# STM32L4P5AEI6 register map
File version: 1.0
Registers are 32-bit, access not given, reset 0x0 unless marked. A register's access mark holds for its fields unless they carry their own. Offsets are from the block's base; [hi:lo] are bit positions; 'fields as' and 'values as' point back to an identical list.

## DMA2D
Base 0x4002B000
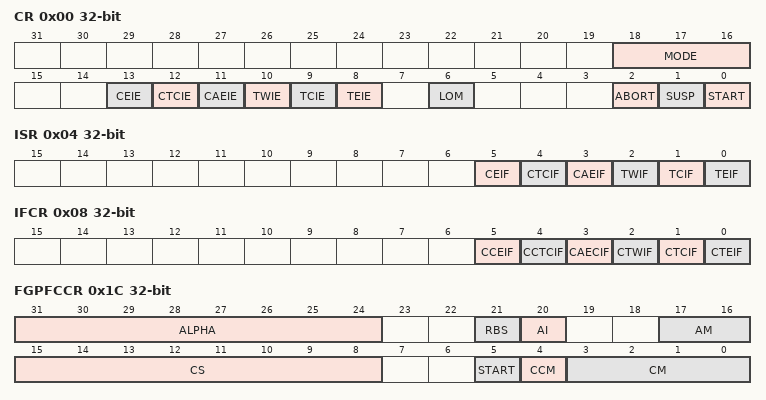
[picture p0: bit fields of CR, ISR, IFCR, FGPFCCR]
0x00 CR
  [18:16] MODE, [13] CEIE, [12] CTCIE, [11] CAEIE, [10] TWIE, [9] TCIE, [8] TEIE, [6] LOM, [2] ABORT, [1] SUSP, [0] START
0x04 ISR
  [5] CEIF, [4] CTCIF, [3] CAEIF, [2] TWIF, [1] TCIF, [0] TEIF
0x08 IFCR
  [5] CCEIF, [4] CCTCIF, [3] CAECIF, [2] CTWIF, [1] CTCIF, [0] CTEIF
0x0C FGMAR
  [31:0] MA
0x10 FGOR
  [15:0] LO
0x14 BGMAR
  [31:0] MA
0x18 BGOR
  [15:0] LO
0x1C FGPFCCR
  [31:24] ALPHA, [21] RBS, [20] AI, [17:16] AM, [15:8] CS, [5] START, [4] CCM, [3:0] CM
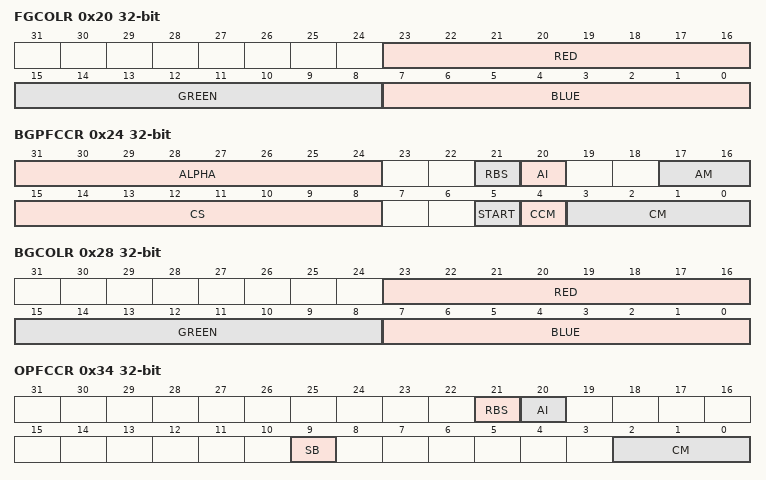
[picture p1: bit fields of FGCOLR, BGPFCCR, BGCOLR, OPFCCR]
0x20 FGCOLR
  [23:16] RED, [15:8] GREEN, [7:0] BLUE
0x24 BGPFCCR
  fields as FGPFCCR
0x28 BGCOLR
  [23:16] RED, [15:8] GREEN, [7:0] BLUE
0x2C FGCMAR
  [31:0] MA
0x30 BGCMAR
  [31:0] MA
0x34 OPFCCR
  [21] RBS, [20] AI, [9] SB, [2:0] CM
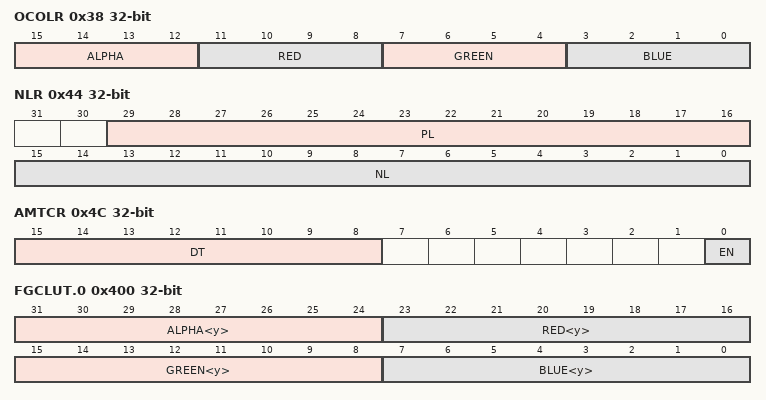
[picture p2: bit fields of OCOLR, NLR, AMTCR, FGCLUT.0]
0x38 OCOLR
  [15:12] ALPHA, [11:8] RED, [7:4] GREEN, [3:0] BLUE
0x3C OMAR
  [31:0] MA
0x40 OOR
  [15:0] LO
0x44 NLR
  [29:16] PL, [15:0] NL
0x48 LWR
  [15:0] LW
0x4C AMTCR
  [15:8] DT, [0] EN
0x400 FGCLUT.0
  [31:24] ALPHA<y>, [23:16] RED<y>, [15:8] GREEN<y>, [7:0] BLUE<y>
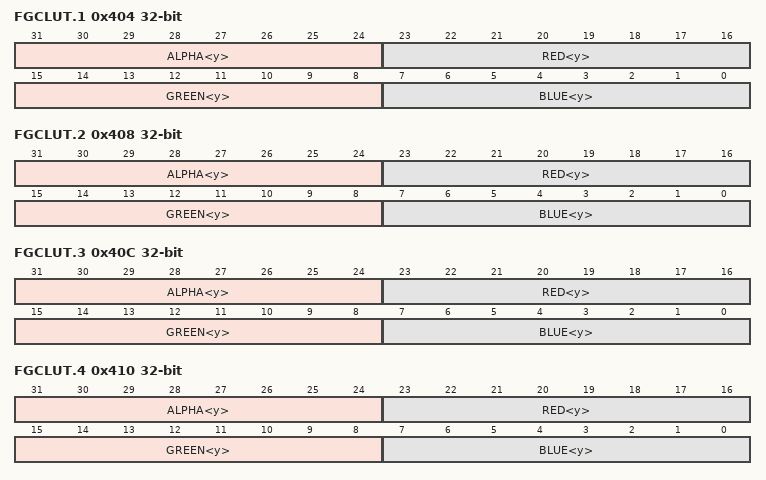
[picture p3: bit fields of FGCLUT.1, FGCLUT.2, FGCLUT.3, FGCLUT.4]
0x404 FGCLUT.1
  [31:24] ALPHA<y>, [23:16] RED<y>, [15:8] GREEN<y>, [7:0] BLUE<y>
0x408 FGCLUT.2
  [31:24] ALPHA<y>, [23:16] RED<y>, [15:8] GREEN<y>, [7:0] BLUE<y>
0x40C FGCLUT.3
  [31:24] ALPHA<y>, [23:16] RED<y>, [15:8] GREEN<y>, [7:0] BLUE<y>
0x410 FGCLUT.4
  [31:24] ALPHA<y>, [23:16] RED<y>, [15:8] GREEN<y>, [7:0] BLUE<y>
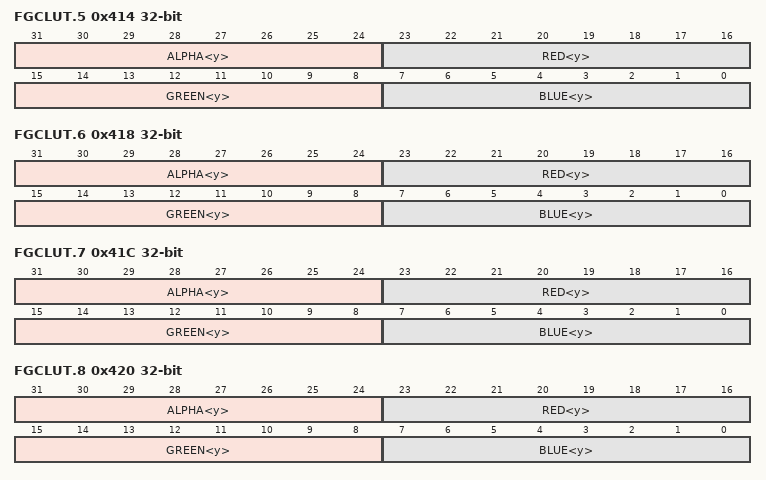
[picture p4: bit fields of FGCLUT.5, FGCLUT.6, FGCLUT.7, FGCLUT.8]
0x414 FGCLUT.5
  [31:24] ALPHA<y>, [23:16] RED<y>, [15:8] GREEN<y>, [7:0] BLUE<y>
0x418 FGCLUT.6
  [31:24] ALPHA<y>, [23:16] RED<y>, [15:8] GREEN<y>, [7:0] BLUE<y>
0x41C FGCLUT.7
  [31:24] ALPHA<y>, [23:16] RED<y>, [15:8] GREEN<y>, [7:0] BLUE<y>
0x420 FGCLUT.8
  [31:24] ALPHA<y>, [23:16] RED<y>, [15:8] GREEN<y>, [7:0] BLUE<y>
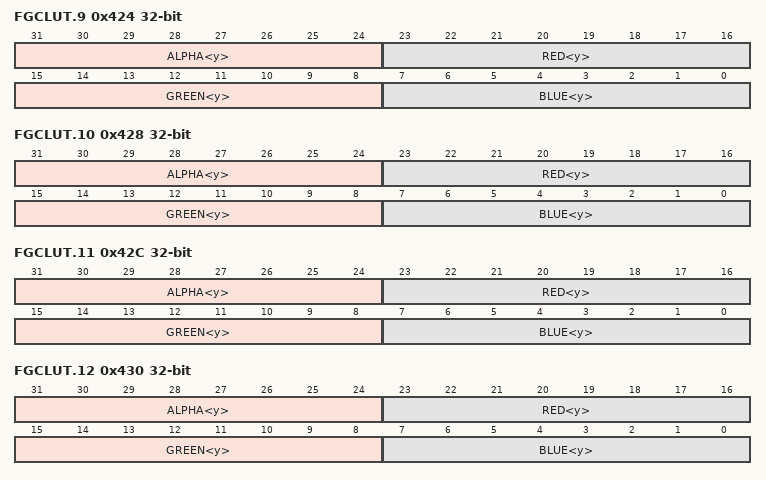
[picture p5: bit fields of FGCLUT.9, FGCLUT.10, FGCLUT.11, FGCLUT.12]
0x424 FGCLUT.9
  [31:24] ALPHA<y>, [23:16] RED<y>, [15:8] GREEN<y>, [7:0] BLUE<y>
0x428 FGCLUT.10
  [31:24] ALPHA<y>, [23:16] RED<y>, [15:8] GREEN<y>, [7:0] BLUE<y>
0x42C FGCLUT.11
  [31:24] ALPHA<y>, [23:16] RED<y>, [15:8] GREEN<y>, [7:0] BLUE<y>
0x430 FGCLUT.12
  [31:24] ALPHA<y>, [23:16] RED<y>, [15:8] GREEN<y>, [7:0] BLUE<y>
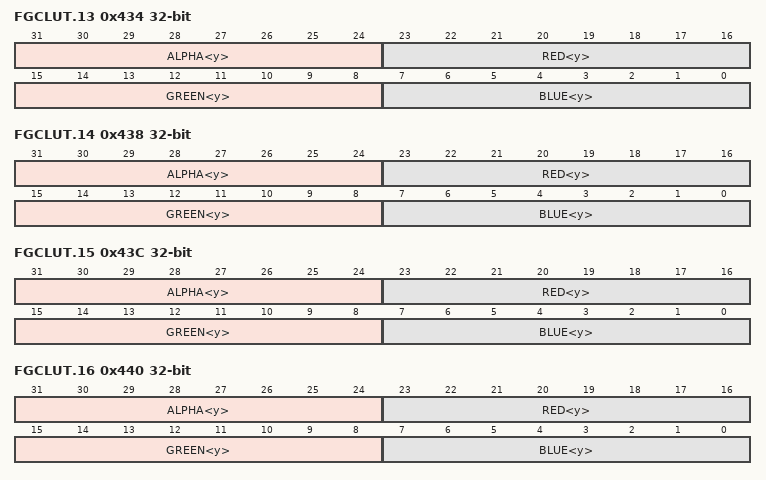
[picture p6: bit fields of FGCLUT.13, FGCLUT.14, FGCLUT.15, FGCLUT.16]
0x434 FGCLUT.13
  [31:24] ALPHA<y>, [23:16] RED<y>, [15:8] GREEN<y>, [7:0] BLUE<y>
0x438 FGCLUT.14
  [31:24] ALPHA<y>, [23:16] RED<y>, [15:8] GREEN<y>, [7:0] BLUE<y>
0x43C FGCLUT.15
  [31:24] ALPHA<y>, [23:16] RED<y>, [15:8] GREEN<y>, [7:0] BLUE<y>
0x440 FGCLUT.16
  [31:24] ALPHA<y>, [23:16] RED<y>, [15:8] GREEN<y>, [7:0] BLUE<y>
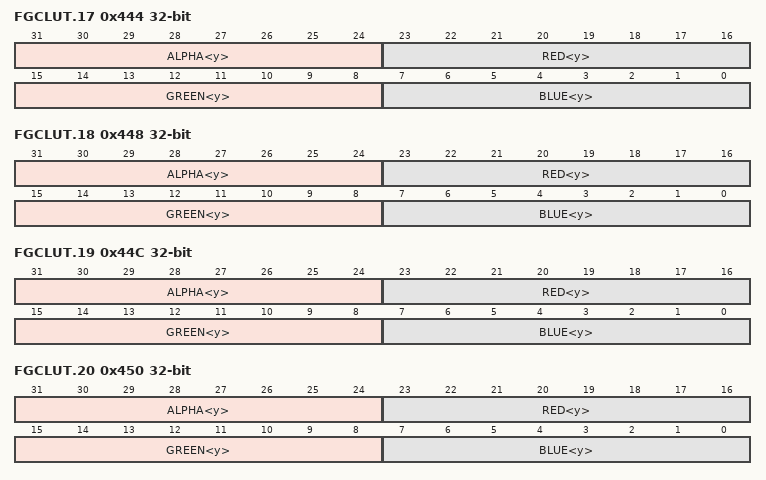
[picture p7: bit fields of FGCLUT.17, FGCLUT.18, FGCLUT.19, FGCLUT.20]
0x444 FGCLUT.17
  [31:24] ALPHA<y>, [23:16] RED<y>, [15:8] GREEN<y>, [7:0] BLUE<y>
0x448 FGCLUT.18
  [31:24] ALPHA<y>, [23:16] RED<y>, [15:8] GREEN<y>, [7:0] BLUE<y>
0x44C FGCLUT.19
  [31:24] ALPHA<y>, [23:16] RED<y>, [15:8] GREEN<y>, [7:0] BLUE<y>
0x450 FGCLUT.20
  [31:24] ALPHA<y>, [23:16] RED<y>, [15:8] GREEN<y>, [7:0] BLUE<y>
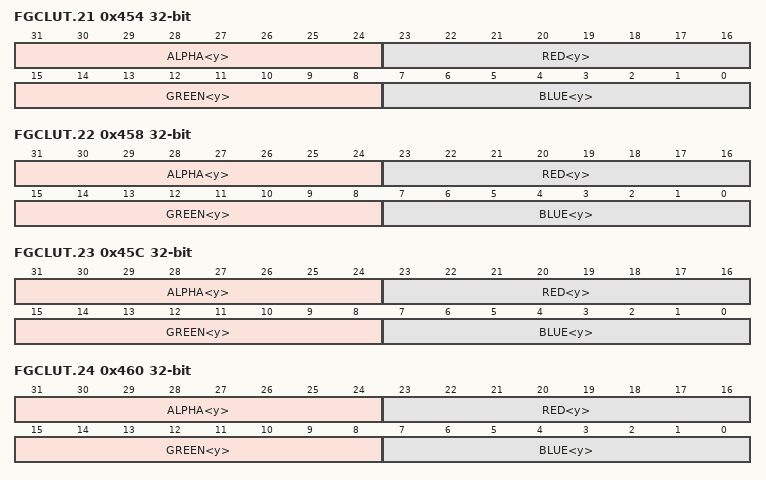
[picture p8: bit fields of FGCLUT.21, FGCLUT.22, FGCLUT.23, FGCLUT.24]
0x454 FGCLUT.21
  [31:24] ALPHA<y>, [23:16] RED<y>, [15:8] GREEN<y>, [7:0] BLUE<y>
0x458 FGCLUT.22
  [31:24] ALPHA<y>, [23:16] RED<y>, [15:8] GREEN<y>, [7:0] BLUE<y>
0x45C FGCLUT.23
  [31:24] ALPHA<y>, [23:16] RED<y>, [15:8] GREEN<y>, [7:0] BLUE<y>
0x460 FGCLUT.24
  [31:24] ALPHA<y>, [23:16] RED<y>, [15:8] GREEN<y>, [7:0] BLUE<y>
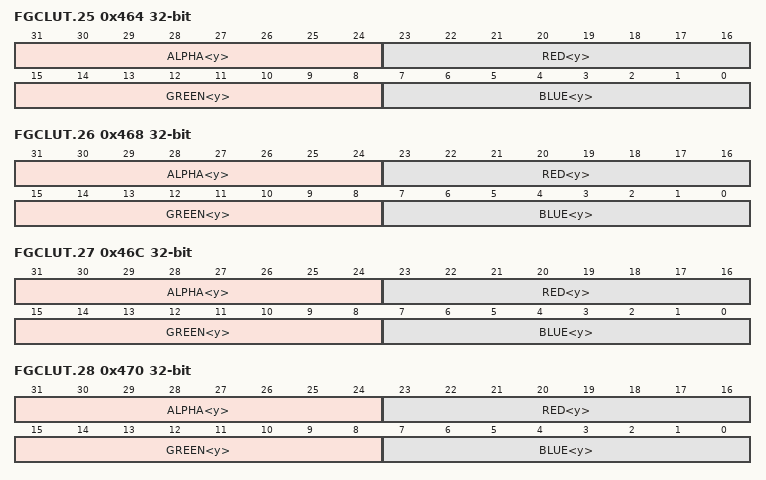
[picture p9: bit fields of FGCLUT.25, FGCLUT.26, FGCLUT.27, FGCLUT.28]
0x464 FGCLUT.25
  [31:24] ALPHA<y>, [23:16] RED<y>, [15:8] GREEN<y>, [7:0] BLUE<y>
0x468 FGCLUT.26
  [31:24] ALPHA<y>, [23:16] RED<y>, [15:8] GREEN<y>, [7:0] BLUE<y>
0x46C FGCLUT.27
  [31:24] ALPHA<y>, [23:16] RED<y>, [15:8] GREEN<y>, [7:0] BLUE<y>
0x470 FGCLUT.28
  [31:24] ALPHA<y>, [23:16] RED<y>, [15:8] GREEN<y>, [7:0] BLUE<y>
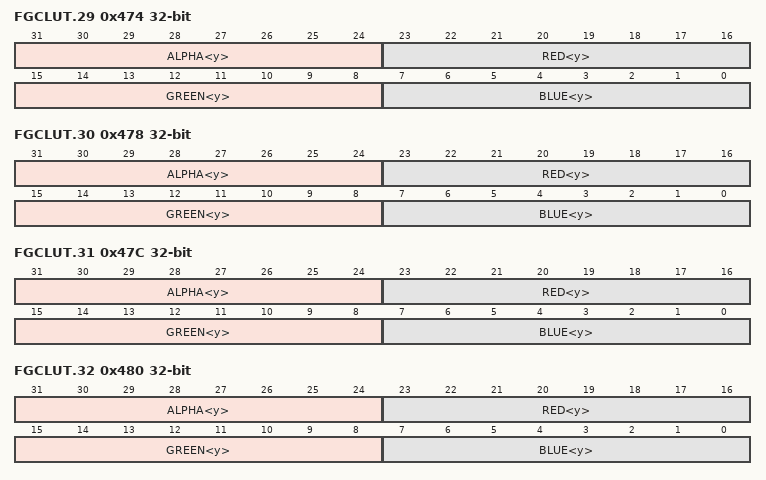
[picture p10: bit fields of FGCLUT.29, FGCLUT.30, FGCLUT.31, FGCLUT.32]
0x474 FGCLUT.29
  [31:24] ALPHA<y>, [23:16] RED<y>, [15:8] GREEN<y>, [7:0] BLUE<y>
0x478 FGCLUT.30
  [31:24] ALPHA<y>, [23:16] RED<y>, [15:8] GREEN<y>, [7:0] BLUE<y>
0x47C FGCLUT.31
  [31:24] ALPHA<y>, [23:16] RED<y>, [15:8] GREEN<y>, [7:0] BLUE<y>
0x480 FGCLUT.32
  [31:24] ALPHA<y>, [23:16] RED<y>, [15:8] GREEN<y>, [7:0] BLUE<y>
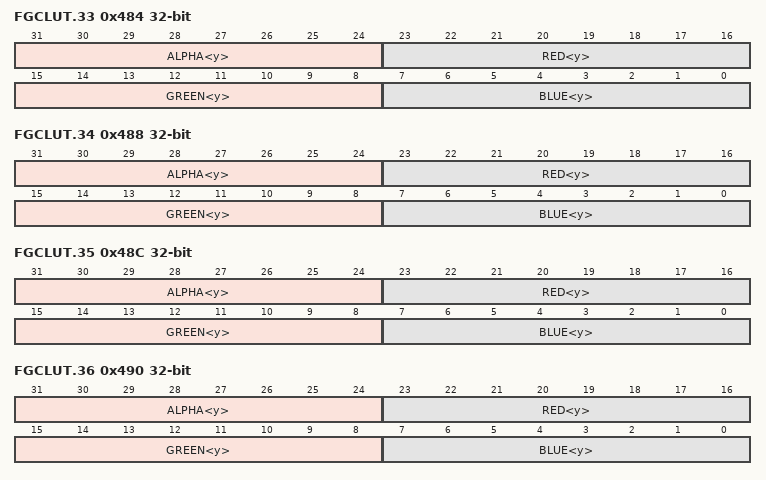
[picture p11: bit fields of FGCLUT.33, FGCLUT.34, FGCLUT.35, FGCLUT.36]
0x484 FGCLUT.33
  [31:24] ALPHA<y>, [23:16] RED<y>, [15:8] GREEN<y>, [7:0] BLUE<y>
0x488 FGCLUT.34
  [31:24] ALPHA<y>, [23:16] RED<y>, [15:8] GREEN<y>, [7:0] BLUE<y>
0x48C FGCLUT.35
  [31:24] ALPHA<y>, [23:16] RED<y>, [15:8] GREEN<y>, [7:0] BLUE<y>
0x490 FGCLUT.36
  [31:24] ALPHA<y>, [23:16] RED<y>, [15:8] GREEN<y>, [7:0] BLUE<y>
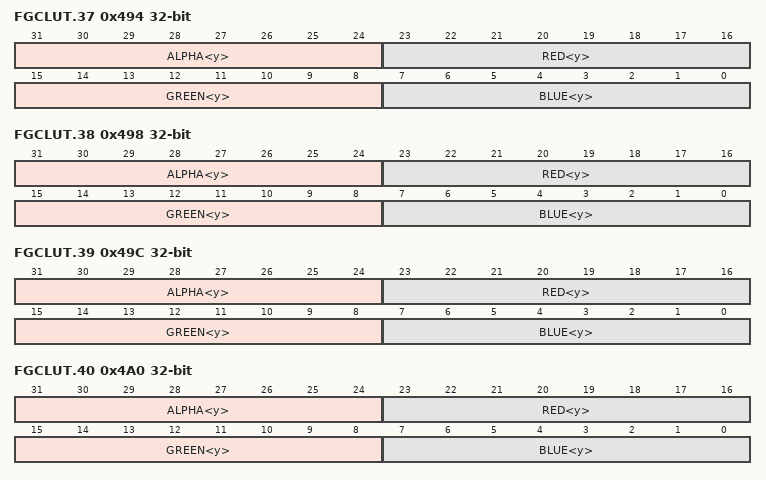
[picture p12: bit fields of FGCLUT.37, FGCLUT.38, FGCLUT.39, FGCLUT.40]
0x494 FGCLUT.37
  [31:24] ALPHA<y>, [23:16] RED<y>, [15:8] GREEN<y>, [7:0] BLUE<y>
0x498 FGCLUT.38
  [31:24] ALPHA<y>, [23:16] RED<y>, [15:8] GREEN<y>, [7:0] BLUE<y>
0x49C FGCLUT.39
  [31:24] ALPHA<y>, [23:16] RED<y>, [15:8] GREEN<y>, [7:0] BLUE<y>
0x4A0 FGCLUT.40
  [31:24] ALPHA<y>, [23:16] RED<y>, [15:8] GREEN<y>, [7:0] BLUE<y>
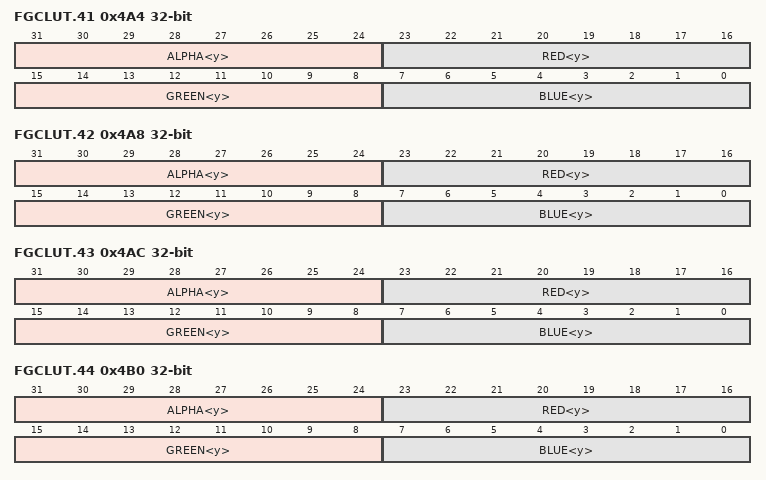
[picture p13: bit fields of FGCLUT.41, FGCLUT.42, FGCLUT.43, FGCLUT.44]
0x4A4 FGCLUT.41
  [31:24] ALPHA<y>, [23:16] RED<y>, [15:8] GREEN<y>, [7:0] BLUE<y>
0x4A8 FGCLUT.42
  [31:24] ALPHA<y>, [23:16] RED<y>, [15:8] GREEN<y>, [7:0] BLUE<y>
0x4AC FGCLUT.43
  [31:24] ALPHA<y>, [23:16] RED<y>, [15:8] GREEN<y>, [7:0] BLUE<y>
0x4B0 FGCLUT.44
  [31:24] ALPHA<y>, [23:16] RED<y>, [15:8] GREEN<y>, [7:0] BLUE<y>
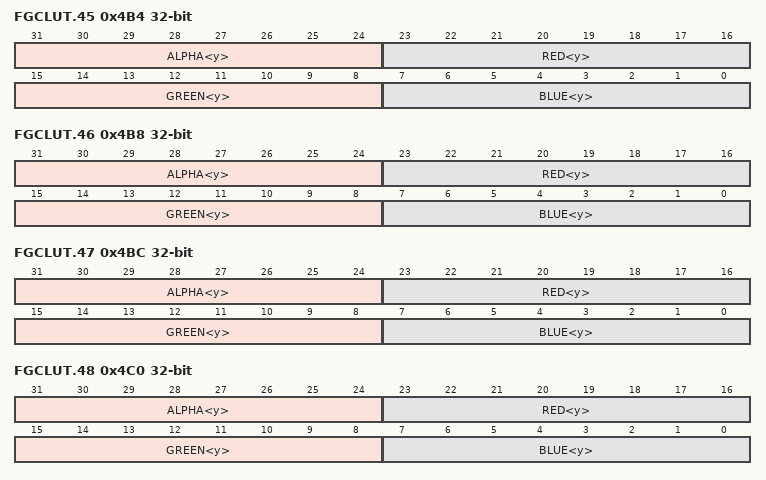
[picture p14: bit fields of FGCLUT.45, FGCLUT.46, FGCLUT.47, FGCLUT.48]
0x4B4 FGCLUT.45
  [31:24] ALPHA<y>, [23:16] RED<y>, [15:8] GREEN<y>, [7:0] BLUE<y>
0x4B8 FGCLUT.46
  [31:24] ALPHA<y>, [23:16] RED<y>, [15:8] GREEN<y>, [7:0] BLUE<y>
0x4BC FGCLUT.47
  [31:24] ALPHA<y>, [23:16] RED<y>, [15:8] GREEN<y>, [7:0] BLUE<y>
0x4C0 FGCLUT.48
  [31:24] ALPHA<y>, [23:16] RED<y>, [15:8] GREEN<y>, [7:0] BLUE<y>
0x4C4 FGCLUT.49
  [31:24] ALPHA<y>, [23:16] RED<y>, [15:8] GREEN<y>, [7:0] BLUE<y>
0x4C8 FGCLUT.50
  [31:24] ALPHA<y>, [23:16] RED<y>, [15:8] GREEN<y>, [7:0] BLUE<y>
0x4CC FGCLUT.51
  [31:24] ALPHA<y>, [23:16] RED<y>, [15:8] GREEN<y>, [7:0] BLUE<y>
0x4D0 FGCLUT.52
  [31:24] ALPHA<y>, [23:16] RED<y>, [15:8] GREEN<y>, [7:0] BLUE<y>
0x4D4 FGCLUT.53
  [31:24] ALPHA<y>, [23:16] RED<y>, [15:8] GREEN<y>, [7:0] BLUE<y>
0x4D8 FGCLUT.54
  [31:24] ALPHA<y>, [23:16] RED<y>, [15:8] GREEN<y>, [7:0] BLUE<y>
0x4DC FGCLUT.55
  [31:24] ALPHA<y>, [23:16] RED<y>, [15:8] GREEN<y>, [7:0] BLUE<y>
0x4E0 FGCLUT.56
  [31:24] ALPHA<y>, [23:16] RED<y>, [15:8] GREEN<y>, [7:0] BLUE<y>
0x4E4 FGCLUT.57
  [31:24] ALPHA<y>, [23:16] RED<y>, [15:8] GREEN<y>, [7:0] BLUE<y>
0x4E8 FGCLUT.58
  [31:24] ALPHA<y>, [23:16] RED<y>, [15:8] GREEN<y>, [7:0] BLUE<y>
0x4EC FGCLUT.59
  [31:24] ALPHA<y>, [23:16] RED<y>, [15:8] GREEN<y>, [7:0] BLUE<y>
0x4F0 FGCLUT.60
  [31:24] ALPHA<y>, [23:16] RED<y>, [15:8] GREEN<y>, [7:0] BLUE<y>
0x4F4 FGCLUT.61
  [31:24] ALPHA<y>, [23:16] RED<y>, [15:8] GREEN<y>, [7:0] BLUE<y>
0x4F8 FGCLUT.62
  [31:24] ALPHA<y>, [23:16] RED<y>, [15:8] GREEN<y>, [7:0] BLUE<y>
0x4FC FGCLUT.63
  [31:24] ALPHA<y>, [23:16] RED<y>, [15:8] GREEN<y>, [7:0] BLUE<y>
0x500 FGCLUT.64
  [31:24] ALPHA<y>, [23:16] RED<y>, [15:8] GREEN<y>, [7:0] BLUE<y>
0x504 FGCLUT.65
  [31:24] ALPHA<y>, [23:16] RED<y>, [15:8] GREEN<y>, [7:0] BLUE<y>
0x508 FGCLUT.66
  [31:24] ALPHA<y>, [23:16] RED<y>, [15:8] GREEN<y>, [7:0] BLUE<y>
0x50C FGCLUT.67
  [31:24] ALPHA<y>, [23:16] RED<y>, [15:8] GREEN<y>, [7:0] BLUE<y>
0x510 FGCLUT.68
  [31:24] ALPHA<y>, [23:16] RED<y>, [15:8] GREEN<y>, [7:0] BLUE<y>
0x514 FGCLUT.69
  [31:24] ALPHA<y>, [23:16] RED<y>, [15:8] GREEN<y>, [7:0] BLUE<y>
0x518 FGCLUT.70
  [31:24] ALPHA<y>, [23:16] RED<y>, [15:8] GREEN<y>, [7:0] BLUE<y>
0x51C FGCLUT.71
  [31:24] ALPHA<y>, [23:16] RED<y>, [15:8] GREEN<y>, [7:0] BLUE<y>
0x520 FGCLUT.72
  [31:24] ALPHA<y>, [23:16] RED<y>, [15:8] GREEN<y>, [7:0] BLUE<y>
0x524 FGCLUT.73
  [31:24] ALPHA<y>, [23:16] RED<y>, [15:8] GREEN<y>, [7:0] BLUE<y>
0x528 FGCLUT.74
  [31:24] ALPHA<y>, [23:16] RED<y>, [15:8] GREEN<y>, [7:0] BLUE<y>
0x52C FGCLUT.75
  [31:24] ALPHA<y>, [23:16] RED<y>, [15:8] GREEN<y>, [7:0] BLUE<y>
0x530 FGCLUT.76
  [31:24] ALPHA<y>, [23:16] RED<y>, [15:8] GREEN<y>, [7:0] BLUE<y>
0x534 FGCLUT.77
  [31:24] ALPHA<y>, [23:16] RED<y>, [15:8] GREEN<y>, [7:0] BLUE<y>
0x538 FGCLUT.78
  [31:24] ALPHA<y>, [23:16] RED<y>, [15:8] GREEN<y>, [7:0] BLUE<y>
0x53C FGCLUT.79
  [31:24] ALPHA<y>, [23:16] RED<y>, [15:8] GREEN<y>, [7:0] BLUE<y>
0x540 FGCLUT.80
  [31:24] ALPHA<y>, [23:16] RED<y>, [15:8] GREEN<y>, [7:0] BLUE<y>
0x544 FGCLUT.81
  [31:24] ALPHA<y>, [23:16] RED<y>, [15:8] GREEN<y>, [7:0] BLUE<y>
0x548 FGCLUT.82
  [31:24] ALPHA<y>, [23:16] RED<y>, [15:8] GREEN<y>, [7:0] BLUE<y>
0x54C FGCLUT.83
  [31:24] ALPHA<y>, [23:16] RED<y>, [15:8] GREEN<y>, [7:0] BLUE<y>
0x550 FGCLUT.84
  [31:24] ALPHA<y>, [23:16] RED<y>, [15:8] GREEN<y>, [7:0] BLUE<y>
0x554 FGCLUT.85
  [31:24] ALPHA<y>, [23:16] RED<y>, [15:8] GREEN<y>, [7:0] BLUE<y>
0x558 FGCLUT.86
  [31:24] ALPHA<y>, [23:16] RED<y>, [15:8] GREEN<y>, [7:0] BLUE<y>
0x55C FGCLUT.87
  [31:24] ALPHA<y>, [23:16] RED<y>, [15:8] GREEN<y>, [7:0] BLUE<y>
0x560 FGCLUT.88
  [31:24] ALPHA<y>, [23:16] RED<y>, [15:8] GREEN<y>, [7:0] BLUE<y>
0x564 FGCLUT.89
  [31:24] ALPHA<y>, [23:16] RED<y>, [15:8] GREEN<y>, [7:0] BLUE<y>
0x568 FGCLUT.90
  [31:24] ALPHA<y>, [23:16] RED<y>, [15:8] GREEN<y>, [7:0] BLUE<y>
0x56C FGCLUT.91
  [31:24] ALPHA<y>, [23:16] RED<y>, [15:8] GREEN<y>, [7:0] BLUE<y>
0x570 FGCLUT.92
  [31:24] ALPHA<y>, [23:16] RED<y>, [15:8] GREEN<y>, [7:0] BLUE<y>
0x574 FGCLUT.93
  [31:24] ALPHA<y>, [23:16] RED<y>, [15:8] GREEN<y>, [7:0] BLUE<y>
0x578 FGCLUT.94
  [31:24] ALPHA<y>, [23:16] RED<y>, [15:8] GREEN<y>, [7:0] BLUE<y>
0x57C FGCLUT.95
  [31:24] ALPHA<y>, [23:16] RED<y>, [15:8] GREEN<y>, [7:0] BLUE<y>
0x580 FGCLUT.96
  [31:24] ALPHA<y>, [23:16] RED<y>, [15:8] GREEN<y>, [7:0] BLUE<y>
0x584 FGCLUT.97
  [31:24] ALPHA<y>, [23:16] RED<y>, [15:8] GREEN<y>, [7:0] BLUE<y>
0x588 FGCLUT.98
  [31:24] ALPHA<y>, [23:16] RED<y>, [15:8] GREEN<y>, [7:0] BLUE<y>
0x58C FGCLUT.99
  [31:24] ALPHA<y>, [23:16] RED<y>, [15:8] GREEN<y>, [7:0] BLUE<y>
0x590 FGCLUT.100
  [31:24] ALPHA<y>, [23:16] RED<y>, [15:8] GREEN<y>, [7:0] BLUE<y>
0x594 FGCLUT.101
  [31:24] ALPHA<y>, [23:16] RED<y>, [15:8] GREEN<y>, [7:0] BLUE<y>
0x598 FGCLUT.102
  [31:24] ALPHA<y>, [23:16] RED<y>, [15:8] GREEN<y>, [7:0] BLUE<y>
0x59C FGCLUT.103
  [31:24] ALPHA<y>, [23:16] RED<y>, [15:8] GREEN<y>, [7:0] BLUE<y>
0x5A0 FGCLUT.104
  [31:24] ALPHA<y>, [23:16] RED<y>, [15:8] GREEN<y>, [7:0] BLUE<y>
0x5A4 FGCLUT.105
  [31:24] ALPHA<y>, [23:16] RED<y>, [15:8] GREEN<y>, [7:0] BLUE<y>
0x5A8 FGCLUT.106
  [31:24] ALPHA<y>, [23:16] RED<y>, [15:8] GREEN<y>, [7:0] BLUE<y>
0x5AC FGCLUT.107
  [31:24] ALPHA<y>, [23:16] RED<y>, [15:8] GREEN<y>, [7:0] BLUE<y>
0x5B0 FGCLUT.108
  [31:24] ALPHA<y>, [23:16] RED<y>, [15:8] GREEN<y>, [7:0] BLUE<y>
0x5B4 FGCLUT.109
  [31:24] ALPHA<y>, [23:16] RED<y>, [15:8] GREEN<y>, [7:0] BLUE<y>
0x5B8 FGCLUT.110
  [31:24] ALPHA<y>, [23:16] RED<y>, [15:8] GREEN<y>, [7:0] BLUE<y>
0x5BC FGCLUT.111
  [31:24] ALPHA<y>, [23:16] RED<y>, [15:8] GREEN<y>, [7:0] BLUE<y>
0x5C0 FGCLUT.112
  [31:24] ALPHA<y>, [23:16] RED<y>, [15:8] GREEN<y>, [7:0] BLUE<y>
0x5C4 FGCLUT.113
  [31:24] ALPHA<y>, [23:16] RED<y>, [15:8] GREEN<y>, [7:0] BLUE<y>
0x5C8 FGCLUT.114
  [31:24] ALPHA<y>, [23:16] RED<y>, [15:8] GREEN<y>, [7:0] BLUE<y>
0x5CC FGCLUT.115
  [31:24] ALPHA<y>, [23:16] RED<y>, [15:8] GREEN<y>, [7:0] BLUE<y>
0x5D0 FGCLUT.116
  [31:24] ALPHA<y>, [23:16] RED<y>, [15:8] GREEN<y>, [7:0] BLUE<y>
0x5D4 FGCLUT.117
  [31:24] ALPHA<y>, [23:16] RED<y>, [15:8] GREEN<y>, [7:0] BLUE<y>
0x5D8 FGCLUT.118
  [31:24] ALPHA<y>, [23:16] RED<y>, [15:8] GREEN<y>, [7:0] BLUE<y>
0x5DC FGCLUT.119
  [31:24] ALPHA<y>, [23:16] RED<y>, [15:8] GREEN<y>, [7:0] BLUE<y>
0x5E0 FGCLUT.120
  [31:24] ALPHA<y>, [23:16] RED<y>, [15:8] GREEN<y>, [7:0] BLUE<y>
0x5E4 FGCLUT.121
  [31:24] ALPHA<y>, [23:16] RED<y>, [15:8] GREEN<y>, [7:0] BLUE<y>
0x5E8 FGCLUT.122
  [31:24] ALPHA<y>, [23:16] RED<y>, [15:8] GREEN<y>, [7:0] BLUE<y>
0x5EC FGCLUT.123
  [31:24] ALPHA<y>, [23:16] RED<y>, [15:8] GREEN<y>, [7:0] BLUE<y>
0x5F0 FGCLUT.124
  [31:24] ALPHA<y>, [23:16] RED<y>, [15:8] GREEN<y>, [7:0] BLUE<y>
0x5F4 FGCLUT.125
  [31:24] ALPHA<y>, [23:16] RED<y>, [15:8] GREEN<y>, [7:0] BLUE<y>
0x5F8 FGCLUT.126
  [31:24] ALPHA<y>, [23:16] RED<y>, [15:8] GREEN<y>, [7:0] BLUE<y>
0x5FC FGCLUT.127
  [31:24] ALPHA<y>, [23:16] RED<y>, [15:8] GREEN<y>, [7:0] BLUE<y>
0x600 FGCLUT.128
  [31:24] ALPHA<y>, [23:16] RED<y>, [15:8] GREEN<y>, [7:0] BLUE<y>
0x604 FGCLUT.129
  [31:24] ALPHA<y>, [23:16] RED<y>, [15:8] GREEN<y>, [7:0] BLUE<y>
0x608 FGCLUT.130
  [31:24] ALPHA<y>, [23:16] RED<y>, [15:8] GREEN<y>, [7:0] BLUE<y>
0x60C FGCLUT.131
  [31:24] ALPHA<y>, [23:16] RED<y>, [15:8] GREEN<y>, [7:0] BLUE<y>
0x610 FGCLUT.132
  [31:24] ALPHA<y>, [23:16] RED<y>, [15:8] GREEN<y>, [7:0] BLUE<y>
0x614 FGCLUT.133
  [31:24] ALPHA<y>, [23:16] RED<y>, [15:8] GREEN<y>, [7:0] BLUE<y>
0x618 FGCLUT.134
  [31:24] ALPHA<y>, [23:16] RED<y>, [15:8] GREEN<y>, [7:0] BLUE<y>
0x61C FGCLUT.135
  [31:24] ALPHA<y>, [23:16] RED<y>, [15:8] GREEN<y>, [7:0] BLUE<y>
0x620 FGCLUT.136
  [31:24] ALPHA<y>, [23:16] RED<y>, [15:8] GREEN<y>, [7:0] BLUE<y>
0x624 FGCLUT.137
  [31:24] ALPHA<y>, [23:16] RED<y>, [15:8] GREEN<y>, [7:0] BLUE<y>
0x628 FGCLUT.138
  [31:24] ALPHA<y>, [23:16] RED<y>, [15:8] GREEN<y>, [7:0] BLUE<y>
0x62C FGCLUT.139
  [31:24] ALPHA<y>, [23:16] RED<y>, [15:8] GREEN<y>, [7:0] BLUE<y>
0x630 FGCLUT.140
  [31:24] ALPHA<y>, [23:16] RED<y>, [15:8] GREEN<y>, [7:0] BLUE<y>
0x634 FGCLUT.141
  [31:24] ALPHA<y>, [23:16] RED<y>, [15:8] GREEN<y>, [7:0] BLUE<y>
0x638 FGCLUT.142
  [31:24] ALPHA<y>, [23:16] RED<y>, [15:8] GREEN<y>, [7:0] BLUE<y>
0x63C FGCLUT.143
  [31:24] ALPHA<y>, [23:16] RED<y>, [15:8] GREEN<y>, [7:0] BLUE<y>
0x640 FGCLUT.144
  [31:24] ALPHA<y>, [23:16] RED<y>, [15:8] GREEN<y>, [7:0] BLUE<y>
0x644 FGCLUT.145
  [31:24] ALPHA<y>, [23:16] RED<y>, [15:8] GREEN<y>, [7:0] BLUE<y>
0x648 FGCLUT.146
  [31:24] ALPHA<y>, [23:16] RED<y>, [15:8] GREEN<y>, [7:0] BLUE<y>
0x64C FGCLUT.147
  [31:24] ALPHA<y>, [23:16] RED<y>, [15:8] GREEN<y>, [7:0] BLUE<y>
0x650 FGCLUT.148
  [31:24] ALPHA<y>, [23:16] RED<y>, [15:8] GREEN<y>, [7:0] BLUE<y>
0x654 FGCLUT.149
  [31:24] ALPHA<y>, [23:16] RED<y>, [15:8] GREEN<y>, [7:0] BLUE<y>
0x658 FGCLUT.150
  [31:24] ALPHA<y>, [23:16] RED<y>, [15:8] GREEN<y>, [7:0] BLUE<y>
0x65C FGCLUT.151
  [31:24] ALPHA<y>, [23:16] RED<y>, [15:8] GREEN<y>, [7:0] BLUE<y>
0x660 FGCLUT.152
  [31:24] ALPHA<y>, [23:16] RED<y>, [15:8] GREEN<y>, [7:0] BLUE<y>
0x664 FGCLUT.153
  [31:24] ALPHA<y>, [23:16] RED<y>, [15:8] GREEN<y>, [7:0] BLUE<y>
0x668 FGCLUT.154
  [31:24] ALPHA<y>, [23:16] RED<y>, [15:8] GREEN<y>, [7:0] BLUE<y>
0x66C FGCLUT.155
  [31:24] ALPHA<y>, [23:16] RED<y>, [15:8] GREEN<y>, [7:0] BLUE<y>
0x670 FGCLUT.156
  [31:24] ALPHA<y>, [23:16] RED<y>, [15:8] GREEN<y>, [7:0] BLUE<y>
0x674 FGCLUT.157
  [31:24] ALPHA<y>, [23:16] RED<y>, [15:8] GREEN<y>, [7:0] BLUE<y>
0x678 FGCLUT.158
  [31:24] ALPHA<y>, [23:16] RED<y>, [15:8] GREEN<y>, [7:0] BLUE<y>
0x67C FGCLUT.159
  [31:24] ALPHA<y>, [23:16] RED<y>, [15:8] GREEN<y>, [7:0] BLUE<y>
0x680 FGCLUT.160
  [31:24] ALPHA<y>, [23:16] RED<y>, [15:8] GREEN<y>, [7:0] BLUE<y>
0x684 FGCLUT.161
  [31:24] ALPHA<y>, [23:16] RED<y>, [15:8] GREEN<y>, [7:0] BLUE<y>
0x688 FGCLUT.162
  [31:24] ALPHA<y>, [23:16] RED<y>, [15:8] GREEN<y>, [7:0] BLUE<y>
0x68C FGCLUT.163
  [31:24] ALPHA<y>, [23:16] RED<y>, [15:8] GREEN<y>, [7:0] BLUE<y>
0x690 FGCLUT.164
  [31:24] ALPHA<y>, [23:16] RED<y>, [15:8] GREEN<y>, [7:0] BLUE<y>
0x694 FGCLUT.165
  [31:24] ALPHA<y>, [23:16] RED<y>, [15:8] GREEN<y>, [7:0] BLUE<y>
0x698 FGCLUT.166
  [31:24] ALPHA<y>, [23:16] RED<y>, [15:8] GREEN<y>, [7:0] BLUE<y>
0x69C FGCLUT.167
  [31:24] ALPHA<y>, [23:16] RED<y>, [15:8] GREEN<y>, [7:0] BLUE<y>
0x6A0 FGCLUT.168
  [31:24] ALPHA<y>, [23:16] RED<y>, [15:8] GREEN<y>, [7:0] BLUE<y>
0x6A4 FGCLUT.169
  [31:24] ALPHA<y>, [23:16] RED<y>, [15:8] GREEN<y>, [7:0] BLUE<y>
0x6A8 FGCLUT.170
  [31:24] ALPHA<y>, [23:16] RED<y>, [15:8] GREEN<y>, [7:0] BLUE<y>
0x6AC FGCLUT.171
  [31:24] ALPHA<y>, [23:16] RED<y>, [15:8] GREEN<y>, [7:0] BLUE<y>
0x6B0 FGCLUT.172
  [31:24] ALPHA<y>, [23:16] RED<y>, [15:8] GREEN<y>, [7:0] BLUE<y>
0x6B4 FGCLUT.173
  [31:24] ALPHA<y>, [23:16] RED<y>, [15:8] GREEN<y>, [7:0] BLUE<y>
0x6B8 FGCLUT.174
  [31:24] ALPHA<y>, [23:16] RED<y>, [15:8] GREEN<y>, [7:0] BLUE<y>
0x6BC FGCLUT.175
  [31:24] ALPHA<y>, [23:16] RED<y>, [15:8] GREEN<y>, [7:0] BLUE<y>
0x6C0 FGCLUT.176
  [31:24] ALPHA<y>, [23:16] RED<y>, [15:8] GREEN<y>, [7:0] BLUE<y>
0x6C4 FGCLUT.177
  [31:24] ALPHA<y>, [23:16] RED<y>, [15:8] GREEN<y>, [7:0] BLUE<y>
0x6C8 FGCLUT.178
  [31:24] ALPHA<y>, [23:16] RED<y>, [15:8] GREEN<y>, [7:0] BLUE<y>
0x6CC FGCLUT.179
  [31:24] ALPHA<y>, [23:16] RED<y>, [15:8] GREEN<y>, [7:0] BLUE<y>
0x6D0 FGCLUT.180
  [31:24] ALPHA<y>, [23:16] RED<y>, [15:8] GREEN<y>, [7:0] BLUE<y>
0x6D4 FGCLUT.181
  [31:24] ALPHA<y>, [23:16] RED<y>, [15:8] GREEN<y>, [7:0] BLUE<y>
0x6D8 FGCLUT.182
  [31:24] ALPHA<y>, [23:16] RED<y>, [15:8] GREEN<y>, [7:0] BLUE<y>
0x6DC FGCLUT.183
  [31:24] ALPHA<y>, [23:16] RED<y>, [15:8] GREEN<y>, [7:0] BLUE<y>
0x6E0 FGCLUT.184
  [31:24] ALPHA<y>, [23:16] RED<y>, [15:8] GREEN<y>, [7:0] BLUE<y>
0x6E4 FGCLUT.185
  [31:24] ALPHA<y>, [23:16] RED<y>, [15:8] GREEN<y>, [7:0] BLUE<y>
0x6E8 FGCLUT.186
  [31:24] ALPHA<y>, [23:16] RED<y>, [15:8] GREEN<y>, [7:0] BLUE<y>
0x6EC FGCLUT.187
  [31:24] ALPHA<y>, [23:16] RED<y>, [15:8] GREEN<y>, [7:0] BLUE<y>
0x6F0 FGCLUT.188
  [31:24] ALPHA<y>, [23:16] RED<y>, [15:8] GREEN<y>, [7:0] BLUE<y>
0x6F4 FGCLUT.189
  [31:24] ALPHA<y>, [23:16] RED<y>, [15:8] GREEN<y>, [7:0] BLUE<y>
0x6F8 FGCLUT.190
  [31:24] ALPHA<y>, [23:16] RED<y>, [15:8] GREEN<y>, [7:0] BLUE<y>
0x6FC FGCLUT.191
  [31:24] ALPHA<y>, [23:16] RED<y>, [15:8] GREEN<y>, [7:0] BLUE<y>
0x700 FGCLUT.192
  [31:24] ALPHA<y>, [23:16] RED<y>, [15:8] GREEN<y>, [7:0] BLUE<y>
0x704 FGCLUT.193
  [31:24] ALPHA<y>, [23:16] RED<y>, [15:8] GREEN<y>, [7:0] BLUE<y>
0x708 FGCLUT.194
  [31:24] ALPHA<y>, [23:16] RED<y>, [15:8] GREEN<y>, [7:0] BLUE<y>
0x70C FGCLUT.195
  [31:24] ALPHA<y>, [23:16] RED<y>, [15:8] GREEN<y>, [7:0] BLUE<y>
0x710 FGCLUT.196
  [31:24] ALPHA<y>, [23:16] RED<y>, [15:8] GREEN<y>, [7:0] BLUE<y>
0x714 FGCLUT.197
  [31:24] ALPHA<y>, [23:16] RED<y>, [15:8] GREEN<y>, [7:0] BLUE<y>
0x718 FGCLUT.198
  [31:24] ALPHA<y>, [23:16] RED<y>, [15:8] GREEN<y>, [7:0] BLUE<y>
0x71C FGCLUT.199
  [31:24] ALPHA<y>, [23:16] RED<y>, [15:8] GREEN<y>, [7:0] BLUE<y>
0x720 FGCLUT.200
  [31:24] ALPHA<y>, [23:16] RED<y>, [15:8] GREEN<y>, [7:0] BLUE<y>
0x724 FGCLUT.201
  [31:24] ALPHA<y>, [23:16] RED<y>, [15:8] GREEN<y>, [7:0] BLUE<y>
0x728 FGCLUT.202
  [31:24] ALPHA<y>, [23:16] RED<y>, [15:8] GREEN<y>, [7:0] BLUE<y>
0x72C FGCLUT.203
  [31:24] ALPHA<y>, [23:16] RED<y>, [15:8] GREEN<y>, [7:0] BLUE<y>
0x730 FGCLUT.204
  [31:24] ALPHA<y>, [23:16] RED<y>, [15:8] GREEN<y>, [7:0] BLUE<y>
0x734 FGCLUT.205
  [31:24] ALPHA<y>, [23:16] RED<y>, [15:8] GREEN<y>, [7:0] BLUE<y>
0x738 FGCLUT.206
  [31:24] ALPHA<y>, [23:16] RED<y>, [15:8] GREEN<y>, [7:0] BLUE<y>
0x73C FGCLUT.207
  [31:24] ALPHA<y>, [23:16] RED<y>, [15:8] GREEN<y>, [7:0] BLUE<y>
0x740 FGCLUT.208
  [31:24] ALPHA<y>, [23:16] RED<y>, [15:8] GREEN<y>, [7:0] BLUE<y>
0x744 FGCLUT.209
  [31:24] ALPHA<y>, [23:16] RED<y>, [15:8] GREEN<y>, [7:0] BLUE<y>
0x748 FGCLUT.210
  [31:24] ALPHA<y>, [23:16] RED<y>, [15:8] GREEN<y>, [7:0] BLUE<y>
0x74C FGCLUT.211
  [31:24] ALPHA<y>, [23:16] RED<y>, [15:8] GREEN<y>, [7:0] BLUE<y>
0x750 FGCLUT.212
  [31:24] ALPHA<y>, [23:16] RED<y>, [15:8] GREEN<y>, [7:0] BLUE<y>
0x754 FGCLUT.213
  [31:24] ALPHA<y>, [23:16] RED<y>, [15:8] GREEN<y>, [7:0] BLUE<y>
0x758 FGCLUT.214
  [31:24] ALPHA<y>, [23:16] RED<y>, [15:8] GREEN<y>, [7:0] BLUE<y>
0x75C FGCLUT.215
  [31:24] ALPHA<y>, [23:16] RED<y>, [15:8] GREEN<y>, [7:0] BLUE<y>
0x760 FGCLUT.216
  [31:24] ALPHA<y>, [23:16] RED<y>, [15:8] GREEN<y>, [7:0] BLUE<y>
0x764 FGCLUT.217
  [31:24] ALPHA<y>, [23:16] RED<y>, [15:8] GREEN<y>, [7:0] BLUE<y>
0x768 FGCLUT.218
  [31:24] ALPHA<y>, [23:16] RED<y>, [15:8] GREEN<y>, [7:0] BLUE<y>
0x76C FGCLUT.219
  [31:24] ALPHA<y>, [23:16] RED<y>, [15:8] GREEN<y>, [7:0] BLUE<y>
0x770 FGCLUT.220
  [31:24] ALPHA<y>, [23:16] RED<y>, [15:8] GREEN<y>, [7:0] BLUE<y>
0x774 FGCLUT.221
  [31:24] ALPHA<y>, [23:16] RED<y>, [15:8] GREEN<y>, [7:0] BLUE<y>
0x778 FGCLUT.222
  [31:24] ALPHA<y>, [23:16] RED<y>, [15:8] GREEN<y>, [7:0] BLUE<y>
0x77C FGCLUT.223
  [31:24] ALPHA<y>, [23:16] RED<y>, [15:8] GREEN<y>, [7:0] BLUE<y>
0x780 FGCLUT.224
  [31:24] ALPHA<y>, [23:16] RED<y>, [15:8] GREEN<y>, [7:0] BLUE<y>
0x784 FGCLUT.225
  [31:24] ALPHA<y>, [23:16] RED<y>, [15:8] GREEN<y>, [7:0] BLUE<y>
0x788 FGCLUT.226
  [31:24] ALPHA<y>, [23:16] RED<y>, [15:8] GREEN<y>, [7:0] BLUE<y>
0x78C FGCLUT.227
  [31:24] ALPHA<y>, [23:16] RED<y>, [15:8] GREEN<y>, [7:0] BLUE<y>
0x790 FGCLUT.228
  [31:24] ALPHA<y>, [23:16] RED<y>, [15:8] GREEN<y>, [7:0] BLUE<y>
0x794 FGCLUT.229
  [31:24] ALPHA<y>, [23:16] RED<y>, [15:8] GREEN<y>, [7:0] BLUE<y>
0x798 FGCLUT.230
  [31:24] ALPHA<y>, [23:16] RED<y>, [15:8] GREEN<y>, [7:0] BLUE<y>
0x79C FGCLUT.231
  [31:24] ALPHA<y>, [23:16] RED<y>, [15:8] GREEN<y>, [7:0] BLUE<y>
0x7A0 FGCLUT.232
  [31:24] ALPHA<y>, [23:16] RED<y>, [15:8] GREEN<y>, [7:0] BLUE<y>
0x7A4 FGCLUT.233
  [31:24] ALPHA<y>, [23:16] RED<y>, [15:8] GREEN<y>, [7:0] BLUE<y>
0x7A8 FGCLUT.234
  [31:24] ALPHA<y>, [23:16] RED<y>, [15:8] GREEN<y>, [7:0] BLUE<y>
0x7AC FGCLUT.235
  [31:24] ALPHA<y>, [23:16] RED<y>, [15:8] GREEN<y>, [7:0] BLUE<y>
0x7B0 FGCLUT.236
  [31:24] ALPHA<y>, [23:16] RED<y>, [15:8] GREEN<y>, [7:0] BLUE<y>
0x7B4 FGCLUT.237
  [31:24] ALPHA<y>, [23:16] RED<y>, [15:8] GREEN<y>, [7:0] BLUE<y>
0x7B8 FGCLUT.238
  [31:24] ALPHA<y>, [23:16] RED<y>, [15:8] GREEN<y>, [7:0] BLUE<y>
0x7BC FGCLUT.239
  [31:24] ALPHA<y>, [23:16] RED<y>, [15:8] GREEN<y>, [7:0] BLUE<y>
0x7C0 FGCLUT.240
  [31:24] ALPHA<y>, [23:16] RED<y>, [15:8] GREEN<y>, [7:0] BLUE<y>
0x7C4 FGCLUT.241
  [31:24] ALPHA<y>, [23:16] RED<y>, [15:8] GREEN<y>, [7:0] BLUE<y>
0x7C8 FGCLUT.242
  [31:24] ALPHA<y>, [23:16] RED<y>, [15:8] GREEN<y>, [7:0] BLUE<y>
0x7CC FGCLUT.243
  [31:24] ALPHA<y>, [23:16] RED<y>, [15:8] GREEN<y>, [7:0] BLUE<y>
0x7D0 FGCLUT.244
  [31:24] ALPHA<y>, [23:16] RED<y>, [15:8] GREEN<y>, [7:0] BLUE<y>
0x7D4 FGCLUT.245
  [31:24] ALPHA<y>, [23:16] RED<y>, [15:8] GREEN<y>, [7:0] BLUE<y>
0x7D8 FGCLUT.246
  [31:24] ALPHA<y>, [23:16] RED<y>, [15:8] GREEN<y>, [7:0] BLUE<y>
0x7DC FGCLUT.247
  [31:24] ALPHA<y>, [23:16] RED<y>, [15:8] GREEN<y>, [7:0] BLUE<y>
0x7E0 FGCLUT.248
  [31:24] ALPHA<y>, [23:16] RED<y>, [15:8] GREEN<y>, [7:0] BLUE<y>
0x7E4 FGCLUT.249
  [31:24] ALPHA<y>, [23:16] RED<y>, [15:8] GREEN<y>, [7:0] BLUE<y>
0x7E8 FGCLUT.250
  [31:24] ALPHA<y>, [23:16] RED<y>, [15:8] GREEN<y>, [7:0] BLUE<y>
0x7EC FGCLUT.251
  [31:24] ALPHA<y>, [23:16] RED<y>, [15:8] GREEN<y>, [7:0] BLUE<y>
0x7F0 FGCLUT.252
  [31:24] ALPHA<y>, [23:16] RED<y>, [15:8] GREEN<y>, [7:0] BLUE<y>
0x7F4 FGCLUT.253
  [31:24] ALPHA<y>, [23:16] RED<y>, [15:8] GREEN<y>, [7:0] BLUE<y>
0x7F8 FGCLUT.254
  [31:24] ALPHA<y>, [23:16] RED<y>, [15:8] GREEN<y>, [7:0] BLUE<y>
0x7FC FGCLUT.255
  [31:24] ALPHA<y>, [23:16] RED<y>, [15:8] GREEN<y>, [7:0] BLUE<y>
0x800 BGCLUT.0
  [31:24] ALPHA<y>, [23:16] RED<y>, [15:8] GREEN<y>, [7:0] BLUE<y>
0x804 BGCLUT.1
  [31:24] ALPHA<y>, [23:16] RED<y>, [15:8] GREEN<y>, [7:0] BLUE<y>
0x808 BGCLUT.2
  [31:24] ALPHA<y>, [23:16] RED<y>, [15:8] GREEN<y>, [7:0] BLUE<y>
0x80C BGCLUT.3
  [31:24] ALPHA<y>, [23:16] RED<y>, [15:8] GREEN<y>, [7:0] BLUE<y>
0x810 BGCLUT.4
  [31:24] ALPHA<y>, [23:16] RED<y>, [15:8] GREEN<y>, [7:0] BLUE<y>
0x814 BGCLUT.5
  [31:24] ALPHA<y>, [23:16] RED<y>, [15:8] GREEN<y>, [7:0] BLUE<y>
0x818 BGCLUT.6
  [31:24] ALPHA<y>, [23:16] RED<y>, [15:8] GREEN<y>, [7:0] BLUE<y>
0x81C BGCLUT.7
  [31:24] ALPHA<y>, [23:16] RED<y>, [15:8] GREEN<y>, [7:0] BLUE<y>
0x820 BGCLUT.8
  [31:24] ALPHA<y>, [23:16] RED<y>, [15:8] GREEN<y>, [7:0] BLUE<y>
0x824 BGCLUT.9
  [31:24] ALPHA<y>, [23:16] RED<y>, [15:8] GREEN<y>, [7:0] BLUE<y>
0x828 BGCLUT.10
  [31:24] ALPHA<y>, [23:16] RED<y>, [15:8] GREEN<y>, [7:0] BLUE<y>
0x82C BGCLUT.11
  [31:24] ALPHA<y>, [23:16] RED<y>, [15:8] GREEN<y>, [7:0] BLUE<y>
0x830 BGCLUT.12
  [31:24] ALPHA<y>, [23:16] RED<y>, [15:8] GREEN<y>, [7:0] BLUE<y>
0x834 BGCLUT.13
  [31:24] ALPHA<y>, [23:16] RED<y>, [15:8] GREEN<y>, [7:0] BLUE<y>
0x838 BGCLUT.14
  [31:24] ALPHA<y>, [23:16] RED<y>, [15:8] GREEN<y>, [7:0] BLUE<y>
0x83C BGCLUT.15
  [31:24] ALPHA<y>, [23:16] RED<y>, [15:8] GREEN<y>, [7:0] BLUE<y>
0x840 BGCLUT.16
  [31:24] ALPHA<y>, [23:16] RED<y>, [15:8] GREEN<y>, [7:0] BLUE<y>
0x844 BGCLUT.17
  [31:24] ALPHA<y>, [23:16] RED<y>, [15:8] GREEN<y>, [7:0] BLUE<y>
0x848 BGCLUT.18
  [31:24] ALPHA<y>, [23:16] RED<y>, [15:8] GREEN<y>, [7:0] BLUE<y>
0x84C BGCLUT.19
  [31:24] ALPHA<y>, [23:16] RED<y>, [15:8] GREEN<y>, [7:0] BLUE<y>
0x850 BGCLUT.20
  [31:24] ALPHA<y>, [23:16] RED<y>, [15:8] GREEN<y>, [7:0] BLUE<y>
0x854 BGCLUT.21
  [31:24] ALPHA<y>, [23:16] RED<y>, [15:8] GREEN<y>, [7:0] BLUE<y>
0x858 BGCLUT.22
  [31:24] ALPHA<y>, [23:16] RED<y>, [15:8] GREEN<y>, [7:0] BLUE<y>
0x85C BGCLUT.23
  [31:24] ALPHA<y>, [23:16] RED<y>, [15:8] GREEN<y>, [7:0] BLUE<y>
0x860 BGCLUT.24
  [31:24] ALPHA<y>, [23:16] RED<y>, [15:8] GREEN<y>, [7:0] BLUE<y>
0x864 BGCLUT.25
  [31:24] ALPHA<y>, [23:16] RED<y>, [15:8] GREEN<y>, [7:0] BLUE<y>
0x868 BGCLUT.26
  [31:24] ALPHA<y>, [23:16] RED<y>, [15:8] GREEN<y>, [7:0] BLUE<y>
0x86C BGCLUT.27
  [31:24] ALPHA<y>, [23:16] RED<y>, [15:8] GREEN<y>, [7:0] BLUE<y>
0x870 BGCLUT.28
  [31:24] ALPHA<y>, [23:16] RED<y>, [15:8] GREEN<y>, [7:0] BLUE<y>
0x874 BGCLUT.29
  [31:24] ALPHA<y>, [23:16] RED<y>, [15:8] GREEN<y>, [7:0] BLUE<y>
0x878 BGCLUT.30
  [31:24] ALPHA<y>, [23:16] RED<y>, [15:8] GREEN<y>, [7:0] BLUE<y>
0x87C BGCLUT.31
  [31:24] ALPHA<y>, [23:16] RED<y>, [15:8] GREEN<y>, [7:0] BLUE<y>
0x880 BGCLUT.32
  [31:24] ALPHA<y>, [23:16] RED<y>, [15:8] GREEN<y>, [7:0] BLUE<y>
0x884 BGCLUT.33
  [31:24] ALPHA<y>, [23:16] RED<y>, [15:8] GREEN<y>, [7:0] BLUE<y>
0x888 BGCLUT.34
  [31:24] ALPHA<y>, [23:16] RED<y>, [15:8] GREEN<y>, [7:0] BLUE<y>
0x88C BGCLUT.35
  [31:24] ALPHA<y>, [23:16] RED<y>, [15:8] GREEN<y>, [7:0] BLUE<y>
0x890 BGCLUT.36
  [31:24] ALPHA<y>, [23:16] RED<y>, [15:8] GREEN<y>, [7:0] BLUE<y>
0x894 BGCLUT.37
  [31:24] ALPHA<y>, [23:16] RED<y>, [15:8] GREEN<y>, [7:0] BLUE<y>
0x898 BGCLUT.38
  [31:24] ALPHA<y>, [23:16] RED<y>, [15:8] GREEN<y>, [7:0] BLUE<y>
0x89C BGCLUT.39
  [31:24] ALPHA<y>, [23:16] RED<y>, [15:8] GREEN<y>, [7:0] BLUE<y>
0x8A0 BGCLUT.40
  [31:24] ALPHA<y>, [23:16] RED<y>, [15:8] GREEN<y>, [7:0] BLUE<y>
0x8A4 BGCLUT.41
  [31:24] ALPHA<y>, [23:16] RED<y>, [15:8] GREEN<y>, [7:0] BLUE<y>
0x8A8 BGCLUT.42
  [31:24] ALPHA<y>, [23:16] RED<y>, [15:8] GREEN<y>, [7:0] BLUE<y>
0x8AC BGCLUT.43
  [31:24] ALPHA<y>, [23:16] RED<y>, [15:8] GREEN<y>, [7:0] BLUE<y>
0x8B0 BGCLUT.44
  [31:24] ALPHA<y>, [23:16] RED<y>, [15:8] GREEN<y>, [7:0] BLUE<y>
0x8B4 BGCLUT.45
  [31:24] ALPHA<y>, [23:16] RED<y>, [15:8] GREEN<y>, [7:0] BLUE<y>
0x8B8 BGCLUT.46
  [31:24] ALPHA<y>, [23:16] RED<y>, [15:8] GREEN<y>, [7:0] BLUE<y>
0x8BC BGCLUT.47
  [31:24] ALPHA<y>, [23:16] RED<y>, [15:8] GREEN<y>, [7:0] BLUE<y>
0x8C0 BGCLUT.48
  [31:24] ALPHA<y>, [23:16] RED<y>, [15:8] GREEN<y>, [7:0] BLUE<y>
0x8C4 BGCLUT.49
  [31:24] ALPHA<y>, [23:16] RED<y>, [15:8] GREEN<y>, [7:0] BLUE<y>
0x8C8 BGCLUT.50
  [31:24] ALPHA<y>, [23:16] RED<y>, [15:8] GREEN<y>, [7:0] BLUE<y>
0x8CC BGCLUT.51
  [31:24] ALPHA<y>, [23:16] RED<y>, [15:8] GREEN<y>, [7:0] BLUE<y>
0x8D0 BGCLUT.52
  [31:24] ALPHA<y>, [23:16] RED<y>, [15:8] GREEN<y>, [7:0] BLUE<y>
0x8D4 BGCLUT.53
  [31:24] ALPHA<y>, [23:16] RED<y>, [15:8] GREEN<y>, [7:0] BLUE<y>
0x8D8 BGCLUT.54
  [31:24] ALPHA<y>, [23:16] RED<y>, [15:8] GREEN<y>, [7:0] BLUE<y>
0x8DC BGCLUT.55
  [31:24] ALPHA<y>, [23:16] RED<y>, [15:8] GREEN<y>, [7:0] BLUE<y>
0x8E0 BGCLUT.56
  [31:24] ALPHA<y>, [23:16] RED<y>, [15:8] GREEN<y>, [7:0] BLUE<y>
0x8E4 BGCLUT.57
  [31:24] ALPHA<y>, [23:16] RED<y>, [15:8] GREEN<y>, [7:0] BLUE<y>
0x8E8 BGCLUT.58
  [31:24] ALPHA<y>, [23:16] RED<y>, [15:8] GREEN<y>, [7:0] BLUE<y>
0x8EC BGCLUT.59
  [31:24] ALPHA<y>, [23:16] RED<y>, [15:8] GREEN<y>, [7:0] BLUE<y>
0x8F0 BGCLUT.60
  [31:24] ALPHA<y>, [23:16] RED<y>, [15:8] GREEN<y>, [7:0] BLUE<y>
0x8F4 BGCLUT.61
  [31:24] ALPHA<y>, [23:16] RED<y>, [15:8] GREEN<y>, [7:0] BLUE<y>
0x8F8 BGCLUT.62
  [31:24] ALPHA<y>, [23:16] RED<y>, [15:8] GREEN<y>, [7:0] BLUE<y>
0x8FC BGCLUT.63
  [31:24] ALPHA<y>, [23:16] RED<y>, [15:8] GREEN<y>, [7:0] BLUE<y>
0x900 BGCLUT.64
  [31:24] ALPHA<y>, [23:16] RED<y>, [15:8] GREEN<y>, [7:0] BLUE<y>
0x904 BGCLUT.65
  [31:24] ALPHA<y>, [23:16] RED<y>, [15:8] GREEN<y>, [7:0] BLUE<y>
0x908 BGCLUT.66
  [31:24] ALPHA<y>, [23:16] RED<y>, [15:8] GREEN<y>, [7:0] BLUE<y>
0x90C BGCLUT.67
  [31:24] ALPHA<y>, [23:16] RED<y>, [15:8] GREEN<y>, [7:0] BLUE<y>
0x910 BGCLUT.68
  [31:24] ALPHA<y>, [23:16] RED<y>, [15:8] GREEN<y>, [7:0] BLUE<y>
0x914 BGCLUT.69
  [31:24] ALPHA<y>, [23:16] RED<y>, [15:8] GREEN<y>, [7:0] BLUE<y>
0x918 BGCLUT.70
  [31:24] ALPHA<y>, [23:16] RED<y>, [15:8] GREEN<y>, [7:0] BLUE<y>
0x91C BGCLUT.71
  [31:24] ALPHA<y>, [23:16] RED<y>, [15:8] GREEN<y>, [7:0] BLUE<y>
0x920 BGCLUT.72
  [31:24] ALPHA<y>, [23:16] RED<y>, [15:8] GREEN<y>, [7:0] BLUE<y>
0x924 BGCLUT.73
  [31:24] ALPHA<y>, [23:16] RED<y>, [15:8] GREEN<y>, [7:0] BLUE<y>
0x928 BGCLUT.74
  [31:24] ALPHA<y>, [23:16] RED<y>, [15:8] GREEN<y>, [7:0] BLUE<y>
0x92C BGCLUT.75
  [31:24] ALPHA<y>, [23:16] RED<y>, [15:8] GREEN<y>, [7:0] BLUE<y>
0x930 BGCLUT.76
  [31:24] ALPHA<y>, [23:16] RED<y>, [15:8] GREEN<y>, [7:0] BLUE<y>
0x934 BGCLUT.77
  [31:24] ALPHA<y>, [23:16] RED<y>, [15:8] GREEN<y>, [7:0] BLUE<y>
0x938 BGCLUT.78
  [31:24] ALPHA<y>, [23:16] RED<y>, [15:8] GREEN<y>, [7:0] BLUE<y>
0x93C BGCLUT.79
  [31:24] ALPHA<y>, [23:16] RED<y>, [15:8] GREEN<y>, [7:0] BLUE<y>
0x940 BGCLUT.80
  [31:24] ALPHA<y>, [23:16] RED<y>, [15:8] GREEN<y>, [7:0] BLUE<y>
0x944 BGCLUT.81
  [31:24] ALPHA<y>, [23:16] RED<y>, [15:8] GREEN<y>, [7:0] BLUE<y>
0x948 BGCLUT.82
  [31:24] ALPHA<y>, [23:16] RED<y>, [15:8] GREEN<y>, [7:0] BLUE<y>
0x94C BGCLUT.83
  [31:24] ALPHA<y>, [23:16] RED<y>, [15:8] GREEN<y>, [7:0] BLUE<y>
0x950 BGCLUT.84
  [31:24] ALPHA<y>, [23:16] RED<y>, [15:8] GREEN<y>, [7:0] BLUE<y>
0x954 BGCLUT.85
  [31:24] ALPHA<y>, [23:16] RED<y>, [15:8] GREEN<y>, [7:0] BLUE<y>
0x958 BGCLUT.86
  [31:24] ALPHA<y>, [23:16] RED<y>, [15:8] GREEN<y>, [7:0] BLUE<y>
0x95C BGCLUT.87
  [31:24] ALPHA<y>, [23:16] RED<y>, [15:8] GREEN<y>, [7:0] BLUE<y>
0x960 BGCLUT.88
  [31:24] ALPHA<y>, [23:16] RED<y>, [15:8] GREEN<y>, [7:0] BLUE<y>
0x964 BGCLUT.89
  [31:24] ALPHA<y>, [23:16] RED<y>, [15:8] GREEN<y>, [7:0] BLUE<y>
0x968 BGCLUT.90
  [31:24] ALPHA<y>, [23:16] RED<y>, [15:8] GREEN<y>, [7:0] BLUE<y>
0x96C BGCLUT.91
  [31:24] ALPHA<y>, [23:16] RED<y>, [15:8] GREEN<y>, [7:0] BLUE<y>
0x970 BGCLUT.92
  [31:24] ALPHA<y>, [23:16] RED<y>, [15:8] GREEN<y>, [7:0] BLUE<y>
0x974 BGCLUT.93
  [31:24] ALPHA<y>, [23:16] RED<y>, [15:8] GREEN<y>, [7:0] BLUE<y>
0x978 BGCLUT.94
  [31:24] ALPHA<y>, [23:16] RED<y>, [15:8] GREEN<y>, [7:0] BLUE<y>
0x97C BGCLUT.95
  [31:24] ALPHA<y>, [23:16] RED<y>, [15:8] GREEN<y>, [7:0] BLUE<y>
0x980 BGCLUT.96
  [31:24] ALPHA<y>, [23:16] RED<y>, [15:8] GREEN<y>, [7:0] BLUE<y>
0x984 BGCLUT.97
  [31:24] ALPHA<y>, [23:16] RED<y>, [15:8] GREEN<y>, [7:0] BLUE<y>
0x988 BGCLUT.98
  [31:24] ALPHA<y>, [23:16] RED<y>, [15:8] GREEN<y>, [7:0] BLUE<y>
0x98C BGCLUT.99
  [31:24] ALPHA<y>, [23:16] RED<y>, [15:8] GREEN<y>, [7:0] BLUE<y>
0x990 BGCLUT.100
  [31:24] ALPHA<y>, [23:16] RED<y>, [15:8] GREEN<y>, [7:0] BLUE<y>
0x994 BGCLUT.101
  [31:24] ALPHA<y>, [23:16] RED<y>, [15:8] GREEN<y>, [7:0] BLUE<y>
0x998 BGCLUT.102
  [31:24] ALPHA<y>, [23:16] RED<y>, [15:8] GREEN<y>, [7:0] BLUE<y>
0x99C BGCLUT.103
  [31:24] ALPHA<y>, [23:16] RED<y>, [15:8] GREEN<y>, [7:0] BLUE<y>
0x9A0 BGCLUT.104
  [31:24] ALPHA<y>, [23:16] RED<y>, [15:8] GREEN<y>, [7:0] BLUE<y>
0x9A4 BGCLUT.105
  [31:24] ALPHA<y>, [23:16] RED<y>, [15:8] GREEN<y>, [7:0] BLUE<y>
0x9A8 BGCLUT.106
  [31:24] ALPHA<y>, [23:16] RED<y>, [15:8] GREEN<y>, [7:0] BLUE<y>
0x9AC BGCLUT.107
  [31:24] ALPHA<y>, [23:16] RED<y>, [15:8] GREEN<y>, [7:0] BLUE<y>
0x9B0 BGCLUT.108
  [31:24] ALPHA<y>, [23:16] RED<y>, [15:8] GREEN<y>, [7:0] BLUE<y>
0x9B4 BGCLUT.109
  [31:24] ALPHA<y>, [23:16] RED<y>, [15:8] GREEN<y>, [7:0] BLUE<y>
0x9B8 BGCLUT.110
  [31:24] ALPHA<y>, [23:16] RED<y>, [15:8] GREEN<y>, [7:0] BLUE<y>
0x9BC BGCLUT.111
  [31:24] ALPHA<y>, [23:16] RED<y>, [15:8] GREEN<y>, [7:0] BLUE<y>
0x9C0 BGCLUT.112
  [31:24] ALPHA<y>, [23:16] RED<y>, [15:8] GREEN<y>, [7:0] BLUE<y>
0x9C4 BGCLUT.113
  [31:24] ALPHA<y>, [23:16] RED<y>, [15:8] GREEN<y>, [7:0] BLUE<y>
0x9C8 BGCLUT.114
  [31:24] ALPHA<y>, [23:16] RED<y>, [15:8] GREEN<y>, [7:0] BLUE<y>
0x9CC BGCLUT.115
  [31:24] ALPHA<y>, [23:16] RED<y>, [15:8] GREEN<y>, [7:0] BLUE<y>
0x9D0 BGCLUT.116
  [31:24] ALPHA<y>, [23:16] RED<y>, [15:8] GREEN<y>, [7:0] BLUE<y>
0x9D4 BGCLUT.117
  [31:24] ALPHA<y>, [23:16] RED<y>, [15:8] GREEN<y>, [7:0] BLUE<y>
0x9D8 BGCLUT.118
  [31:24] ALPHA<y>, [23:16] RED<y>, [15:8] GREEN<y>, [7:0] BLUE<y>
0x9DC BGCLUT.119
  [31:24] ALPHA<y>, [23:16] RED<y>, [15:8] GREEN<y>, [7:0] BLUE<y>
0x9E0 BGCLUT.120
  [31:24] ALPHA<y>, [23:16] RED<y>, [15:8] GREEN<y>, [7:0] BLUE<y>
0x9E4 BGCLUT.121
  [31:24] ALPHA<y>, [23:16] RED<y>, [15:8] GREEN<y>, [7:0] BLUE<y>
0x9E8 BGCLUT.122
  [31:24] ALPHA<y>, [23:16] RED<y>, [15:8] GREEN<y>, [7:0] BLUE<y>
0x9EC BGCLUT.123
  [31:24] ALPHA<y>, [23:16] RED<y>, [15:8] GREEN<y>, [7:0] BLUE<y>
0x9F0 BGCLUT.124
  [31:24] ALPHA<y>, [23:16] RED<y>, [15:8] GREEN<y>, [7:0] BLUE<y>
0x9F4 BGCLUT.125
  [31:24] ALPHA<y>, [23:16] RED<y>, [15:8] GREEN<y>, [7:0] BLUE<y>
0x9F8 BGCLUT.126
  [31:24] ALPHA<y>, [23:16] RED<y>, [15:8] GREEN<y>, [7:0] BLUE<y>
0x9FC BGCLUT.127
  [31:24] ALPHA<y>, [23:16] RED<y>, [15:8] GREEN<y>, [7:0] BLUE<y>
0xA00 BGCLUT.128
  [31:24] ALPHA<y>, [23:16] RED<y>, [15:8] GREEN<y>, [7:0] BLUE<y>
0xA04 BGCLUT.129
  [31:24] ALPHA<y>, [23:16] RED<y>, [15:8] GREEN<y>, [7:0] BLUE<y>
0xA08 BGCLUT.130
  [31:24] ALPHA<y>, [23:16] RED<y>, [15:8] GREEN<y>, [7:0] BLUE<y>
0xA0C BGCLUT.131
  [31:24] ALPHA<y>, [23:16] RED<y>, [15:8] GREEN<y>, [7:0] BLUE<y>
0xA10 BGCLUT.132
  [31:24] ALPHA<y>, [23:16] RED<y>, [15:8] GREEN<y>, [7:0] BLUE<y>
0xA14 BGCLUT.133
  [31:24] ALPHA<y>, [23:16] RED<y>, [15:8] GREEN<y>, [7:0] BLUE<y>
0xA18 BGCLUT.134
  [31:24] ALPHA<y>, [23:16] RED<y>, [15:8] GREEN<y>, [7:0] BLUE<y>
0xA1C BGCLUT.135
  [31:24] ALPHA<y>, [23:16] RED<y>, [15:8] GREEN<y>, [7:0] BLUE<y>
0xA20 BGCLUT.136
  [31:24] ALPHA<y>, [23:16] RED<y>, [15:8] GREEN<y>, [7:0] BLUE<y>
0xA24 BGCLUT.137
  [31:24] ALPHA<y>, [23:16] RED<y>, [15:8] GREEN<y>, [7:0] BLUE<y>
0xA28 BGCLUT.138
  [31:24] ALPHA<y>, [23:16] RED<y>, [15:8] GREEN<y>, [7:0] BLUE<y>
0xA2C BGCLUT.139
  [31:24] ALPHA<y>, [23:16] RED<y>, [15:8] GREEN<y>, [7:0] BLUE<y>
0xA30 BGCLUT.140
  [31:24] ALPHA<y>, [23:16] RED<y>, [15:8] GREEN<y>, [7:0] BLUE<y>
0xA34 BGCLUT.141
  [31:24] ALPHA<y>, [23:16] RED<y>, [15:8] GREEN<y>, [7:0] BLUE<y>
0xA38 BGCLUT.142
  [31:24] ALPHA<y>, [23:16] RED<y>, [15:8] GREEN<y>, [7:0] BLUE<y>
0xA3C BGCLUT.143
  [31:24] ALPHA<y>, [23:16] RED<y>, [15:8] GREEN<y>, [7:0] BLUE<y>
0xA40 BGCLUT.144
  [31:24] ALPHA<y>, [23:16] RED<y>, [15:8] GREEN<y>, [7:0] BLUE<y>
0xA44 BGCLUT.145
  [31:24] ALPHA<y>, [23:16] RED<y>, [15:8] GREEN<y>, [7:0] BLUE<y>
0xA48 BGCLUT.146
  [31:24] ALPHA<y>, [23:16] RED<y>, [15:8] GREEN<y>, [7:0] BLUE<y>
0xA4C BGCLUT.147
  [31:24] ALPHA<y>, [23:16] RED<y>, [15:8] GREEN<y>, [7:0] BLUE<y>
0xA50 BGCLUT.148
  [31:24] ALPHA<y>, [23:16] RED<y>, [15:8] GREEN<y>, [7:0] BLUE<y>
0xA54 BGCLUT.149
  [31:24] ALPHA<y>, [23:16] RED<y>, [15:8] GREEN<y>, [7:0] BLUE<y>
0xA58 BGCLUT.150
  [31:24] ALPHA<y>, [23:16] RED<y>, [15:8] GREEN<y>, [7:0] BLUE<y>
0xA5C BGCLUT.151
  [31:24] ALPHA<y>, [23:16] RED<y>, [15:8] GREEN<y>, [7:0] BLUE<y>
0xA60 BGCLUT.152
  [31:24] ALPHA<y>, [23:16] RED<y>, [15:8] GREEN<y>, [7:0] BLUE<y>
0xA64 BGCLUT.153
  [31:24] ALPHA<y>, [23:16] RED<y>, [15:8] GREEN<y>, [7:0] BLUE<y>
0xA68 BGCLUT.154
  [31:24] ALPHA<y>, [23:16] RED<y>, [15:8] GREEN<y>, [7:0] BLUE<y>
0xA6C BGCLUT.155
  [31:24] ALPHA<y>, [23:16] RED<y>, [15:8] GREEN<y>, [7:0] BLUE<y>
0xA70 BGCLUT.156
  [31:24] ALPHA<y>, [23:16] RED<y>, [15:8] GREEN<y>, [7:0] BLUE<y>
0xA74 BGCLUT.157
  [31:24] ALPHA<y>, [23:16] RED<y>, [15:8] GREEN<y>, [7:0] BLUE<y>
0xA78 BGCLUT.158
  [31:24] ALPHA<y>, [23:16] RED<y>, [15:8] GREEN<y>, [7:0] BLUE<y>
0xA7C BGCLUT.159
  [31:24] ALPHA<y>, [23:16] RED<y>, [15:8] GREEN<y>, [7:0] BLUE<y>
0xA80 BGCLUT.160
  [31:24] ALPHA<y>, [23:16] RED<y>, [15:8] GREEN<y>, [7:0] BLUE<y>
0xA84 BGCLUT.161
  [31:24] ALPHA<y>, [23:16] RED<y>, [15:8] GREEN<y>, [7:0] BLUE<y>
0xA88 BGCLUT.162
  [31:24] ALPHA<y>, [23:16] RED<y>, [15:8] GREEN<y>, [7:0] BLUE<y>
0xA8C BGCLUT.163
  [31:24] ALPHA<y>, [23:16] RED<y>, [15:8] GREEN<y>, [7:0] BLUE<y>
0xA90 BGCLUT.164
  [31:24] ALPHA<y>, [23:16] RED<y>, [15:8] GREEN<y>, [7:0] BLUE<y>
0xA94 BGCLUT.165
  [31:24] ALPHA<y>, [23:16] RED<y>, [15:8] GREEN<y>, [7:0] BLUE<y>
0xA98 BGCLUT.166
  [31:24] ALPHA<y>, [23:16] RED<y>, [15:8] GREEN<y>, [7:0] BLUE<y>
0xA9C BGCLUT.167
  [31:24] ALPHA<y>, [23:16] RED<y>, [15:8] GREEN<y>, [7:0] BLUE<y>
0xAA0 BGCLUT.168
  [31:24] ALPHA<y>, [23:16] RED<y>, [15:8] GREEN<y>, [7:0] BLUE<y>
0xAA4 BGCLUT.169
  [31:24] ALPHA<y>, [23:16] RED<y>, [15:8] GREEN<y>, [7:0] BLUE<y>
0xAA8 BGCLUT.170
  [31:24] ALPHA<y>, [23:16] RED<y>, [15:8] GREEN<y>, [7:0] BLUE<y>
0xAAC BGCLUT.171
  [31:24] ALPHA<y>, [23:16] RED<y>, [15:8] GREEN<y>, [7:0] BLUE<y>
0xAB0 BGCLUT.172
  [31:24] ALPHA<y>, [23:16] RED<y>, [15:8] GREEN<y>, [7:0] BLUE<y>
0xAB4 BGCLUT.173
  [31:24] ALPHA<y>, [23:16] RED<y>, [15:8] GREEN<y>, [7:0] BLUE<y>
0xAB8 BGCLUT.174
  [31:24] ALPHA<y>, [23:16] RED<y>, [15:8] GREEN<y>, [7:0] BLUE<y>
0xABC BGCLUT.175
  [31:24] ALPHA<y>, [23:16] RED<y>, [15:8] GREEN<y>, [7:0] BLUE<y>
0xAC0 BGCLUT.176
  [31:24] ALPHA<y>, [23:16] RED<y>, [15:8] GREEN<y>, [7:0] BLUE<y>
0xAC4 BGCLUT.177
  [31:24] ALPHA<y>, [23:16] RED<y>, [15:8] GREEN<y>, [7:0] BLUE<y>
0xAC8 BGCLUT.178
  [31:24] ALPHA<y>, [23:16] RED<y>, [15:8] GREEN<y>, [7:0] BLUE<y>
0xACC BGCLUT.179
  [31:24] ALPHA<y>, [23:16] RED<y>, [15:8] GREEN<y>, [7:0] BLUE<y>
0xAD0 BGCLUT.180
  [31:24] ALPHA<y>, [23:16] RED<y>, [15:8] GREEN<y>, [7:0] BLUE<y>
0xAD4 BGCLUT.181
  [31:24] ALPHA<y>, [23:16] RED<y>, [15:8] GREEN<y>, [7:0] BLUE<y>
0xAD8 BGCLUT.182
  [31:24] ALPHA<y>, [23:16] RED<y>, [15:8] GREEN<y>, [7:0] BLUE<y>
0xADC BGCLUT.183
  [31:24] ALPHA<y>, [23:16] RED<y>, [15:8] GREEN<y>, [7:0] BLUE<y>
0xAE0 BGCLUT.184
  [31:24] ALPHA<y>, [23:16] RED<y>, [15:8] GREEN<y>, [7:0] BLUE<y>
0xAE4 BGCLUT.185
  [31:24] ALPHA<y>, [23:16] RED<y>, [15:8] GREEN<y>, [7:0] BLUE<y>
0xAE8 BGCLUT.186
  [31:24] ALPHA<y>, [23:16] RED<y>, [15:8] GREEN<y>, [7:0] BLUE<y>
0xAEC BGCLUT.187
  [31:24] ALPHA<y>, [23:16] RED<y>, [15:8] GREEN<y>, [7:0] BLUE<y>
0xAF0 BGCLUT.188
  [31:24] ALPHA<y>, [23:16] RED<y>, [15:8] GREEN<y>, [7:0] BLUE<y>
0xAF4 BGCLUT.189
  [31:24] ALPHA<y>, [23:16] RED<y>, [15:8] GREEN<y>, [7:0] BLUE<y>
0xAF8 BGCLUT.190
  [31:24] ALPHA<y>, [23:16] RED<y>, [15:8] GREEN<y>, [7:0] BLUE<y>
0xAFC BGCLUT.191
  [31:24] ALPHA<y>, [23:16] RED<y>, [15:8] GREEN<y>, [7:0] BLUE<y>
0xB00 BGCLUT.192
  [31:24] ALPHA<y>, [23:16] RED<y>, [15:8] GREEN<y>, [7:0] BLUE<y>
0xB04 BGCLUT.193
  [31:24] ALPHA<y>, [23:16] RED<y>, [15:8] GREEN<y>, [7:0] BLUE<y>
0xB08 BGCLUT.194
  [31:24] ALPHA<y>, [23:16] RED<y>, [15:8] GREEN<y>, [7:0] BLUE<y>
0xB0C BGCLUT.195
  [31:24] ALPHA<y>, [23:16] RED<y>, [15:8] GREEN<y>, [7:0] BLUE<y>
0xB10 BGCLUT.196
  [31:24] ALPHA<y>, [23:16] RED<y>, [15:8] GREEN<y>, [7:0] BLUE<y>
0xB14 BGCLUT.197
  [31:24] ALPHA<y>, [23:16] RED<y>, [15:8] GREEN<y>, [7:0] BLUE<y>
0xB18 BGCLUT.198
  [31:24] ALPHA<y>, [23:16] RED<y>, [15:8] GREEN<y>, [7:0] BLUE<y>
0xB1C BGCLUT.199
  [31:24] ALPHA<y>, [23:16] RED<y>, [15:8] GREEN<y>, [7:0] BLUE<y>
0xB20 BGCLUT.200
  [31:24] ALPHA<y>, [23:16] RED<y>, [15:8] GREEN<y>, [7:0] BLUE<y>
0xB24 BGCLUT.201
  [31:24] ALPHA<y>, [23:16] RED<y>, [15:8] GREEN<y>, [7:0] BLUE<y>
0xB28 BGCLUT.202
  [31:24] ALPHA<y>, [23:16] RED<y>, [15:8] GREEN<y>, [7:0] BLUE<y>
0xB2C BGCLUT.203
  [31:24] ALPHA<y>, [23:16] RED<y>, [15:8] GREEN<y>, [7:0] BLUE<y>
0xB30 BGCLUT.204
  [31:24] ALPHA<y>, [23:16] RED<y>, [15:8] GREEN<y>, [7:0] BLUE<y>
0xB34 BGCLUT.205
  [31:24] ALPHA<y>, [23:16] RED<y>, [15:8] GREEN<y>, [7:0] BLUE<y>
0xB38 BGCLUT.206
  [31:24] ALPHA<y>, [23:16] RED<y>, [15:8] GREEN<y>, [7:0] BLUE<y>
0xB3C BGCLUT.207
  [31:24] ALPHA<y>, [23:16] RED<y>, [15:8] GREEN<y>, [7:0] BLUE<y>
0xB40 BGCLUT.208
  [31:24] ALPHA<y>, [23:16] RED<y>, [15:8] GREEN<y>, [7:0] BLUE<y>
0xB44 BGCLUT.209
  [31:24] ALPHA<y>, [23:16] RED<y>, [15:8] GREEN<y>, [7:0] BLUE<y>
0xB48 BGCLUT.210
  [31:24] ALPHA<y>, [23:16] RED<y>, [15:8] GREEN<y>, [7:0] BLUE<y>
0xB4C BGCLUT.211
  [31:24] ALPHA<y>, [23:16] RED<y>, [15:8] GREEN<y>, [7:0] BLUE<y>
0xB50 BGCLUT.212
  [31:24] ALPHA<y>, [23:16] RED<y>, [15:8] GREEN<y>, [7:0] BLUE<y>
0xB54 BGCLUT.213
  [31:24] ALPHA<y>, [23:16] RED<y>, [15:8] GREEN<y>, [7:0] BLUE<y>
0xB58 BGCLUT.214
  [31:24] ALPHA<y>, [23:16] RED<y>, [15:8] GREEN<y>, [7:0] BLUE<y>
0xB5C BGCLUT.215
  [31:24] ALPHA<y>, [23:16] RED<y>, [15:8] GREEN<y>, [7:0] BLUE<y>
0xB60 BGCLUT.216
  [31:24] ALPHA<y>, [23:16] RED<y>, [15:8] GREEN<y>, [7:0] BLUE<y>
0xB64 BGCLUT.217
  [31:24] ALPHA<y>, [23:16] RED<y>, [15:8] GREEN<y>, [7:0] BLUE<y>
0xB68 BGCLUT.218
  [31:24] ALPHA<y>, [23:16] RED<y>, [15:8] GREEN<y>, [7:0] BLUE<y>
0xB6C BGCLUT.219
  [31:24] ALPHA<y>, [23:16] RED<y>, [15:8] GREEN<y>, [7:0] BLUE<y>
0xB70 BGCLUT.220
  [31:24] ALPHA<y>, [23:16] RED<y>, [15:8] GREEN<y>, [7:0] BLUE<y>
0xB74 BGCLUT.221
  [31:24] ALPHA<y>, [23:16] RED<y>, [15:8] GREEN<y>, [7:0] BLUE<y>
0xB78 BGCLUT.222
  [31:24] ALPHA<y>, [23:16] RED<y>, [15:8] GREEN<y>, [7:0] BLUE<y>
0xB7C BGCLUT.223
  [31:24] ALPHA<y>, [23:16] RED<y>, [15:8] GREEN<y>, [7:0] BLUE<y>
0xB80 BGCLUT.224
  [31:24] ALPHA<y>, [23:16] RED<y>, [15:8] GREEN<y>, [7:0] BLUE<y>
0xB84 BGCLUT.225
  [31:24] ALPHA<y>, [23:16] RED<y>, [15:8] GREEN<y>, [7:0] BLUE<y>
0xB88 BGCLUT.226
  [31:24] ALPHA<y>, [23:16] RED<y>, [15:8] GREEN<y>, [7:0] BLUE<y>
0xB8C BGCLUT.227
  [31:24] ALPHA<y>, [23:16] RED<y>, [15:8] GREEN<y>, [7:0] BLUE<y>
0xB90 BGCLUT.228
  [31:24] ALPHA<y>, [23:16] RED<y>, [15:8] GREEN<y>, [7:0] BLUE<y>
0xB94 BGCLUT.229
  [31:24] ALPHA<y>, [23:16] RED<y>, [15:8] GREEN<y>, [7:0] BLUE<y>
0xB98 BGCLUT.230
  [31:24] ALPHA<y>, [23:16] RED<y>, [15:8] GREEN<y>, [7:0] BLUE<y>
0xB9C BGCLUT.231
  [31:24] ALPHA<y>, [23:16] RED<y>, [15:8] GREEN<y>, [7:0] BLUE<y>
0xBA0 BGCLUT.232
  [31:24] ALPHA<y>, [23:16] RED<y>, [15:8] GREEN<y>, [7:0] BLUE<y>
0xBA4 BGCLUT.233
  [31:24] ALPHA<y>, [23:16] RED<y>, [15:8] GREEN<y>, [7:0] BLUE<y>
0xBA8 BGCLUT.234
  [31:24] ALPHA<y>, [23:16] RED<y>, [15:8] GREEN<y>, [7:0] BLUE<y>
0xBAC BGCLUT.235
  [31:24] ALPHA<y>, [23:16] RED<y>, [15:8] GREEN<y>, [7:0] BLUE<y>
0xBB0 BGCLUT.236
  [31:24] ALPHA<y>, [23:16] RED<y>, [15:8] GREEN<y>, [7:0] BLUE<y>
0xBB4 BGCLUT.237
  [31:24] ALPHA<y>, [23:16] RED<y>, [15:8] GREEN<y>, [7:0] BLUE<y>
0xBB8 BGCLUT.238
  [31:24] ALPHA<y>, [23:16] RED<y>, [15:8] GREEN<y>, [7:0] BLUE<y>
0xBBC BGCLUT.239
  [31:24] ALPHA<y>, [23:16] RED<y>, [15:8] GREEN<y>, [7:0] BLUE<y>
0xBC0 BGCLUT.240
  [31:24] ALPHA<y>, [23:16] RED<y>, [15:8] GREEN<y>, [7:0] BLUE<y>
0xBC4 BGCLUT.241
  [31:24] ALPHA<y>, [23:16] RED<y>, [15:8] GREEN<y>, [7:0] BLUE<y>
0xBC8 BGCLUT.242
  [31:24] ALPHA<y>, [23:16] RED<y>, [15:8] GREEN<y>, [7:0] BLUE<y>
0xBCC BGCLUT.243
  [31:24] ALPHA<y>, [23:16] RED<y>, [15:8] GREEN<y>, [7:0] BLUE<y>
0xBD0 BGCLUT.244
  [31:24] ALPHA<y>, [23:16] RED<y>, [15:8] GREEN<y>, [7:0] BLUE<y>
0xBD4 BGCLUT.245
  [31:24] ALPHA<y>, [23:16] RED<y>, [15:8] GREEN<y>, [7:0] BLUE<y>
0xBD8 BGCLUT.246
  [31:24] ALPHA<y>, [23:16] RED<y>, [15:8] GREEN<y>, [7:0] BLUE<y>
0xBDC BGCLUT.247
  [31:24] ALPHA<y>, [23:16] RED<y>, [15:8] GREEN<y>, [7:0] BLUE<y>
0xBE0 BGCLUT.248
  [31:24] ALPHA<y>, [23:16] RED<y>, [15:8] GREEN<y>, [7:0] BLUE<y>
0xBE4 BGCLUT.249
  [31:24] ALPHA<y>, [23:16] RED<y>, [15:8] GREEN<y>, [7:0] BLUE<y>
0xBE8 BGCLUT.250
  [31:24] ALPHA<y>, [23:16] RED<y>, [15:8] GREEN<y>, [7:0] BLUE<y>
0xBEC BGCLUT.251
  [31:24] ALPHA<y>, [23:16] RED<y>, [15:8] GREEN<y>, [7:0] BLUE<y>
0xBF0 BGCLUT.252
  [31:24] ALPHA<y>, [23:16] RED<y>, [15:8] GREEN<y>, [7:0] BLUE<y>
0xBF4 BGCLUT.253
  [31:24] ALPHA<y>, [23:16] RED<y>, [15:8] GREEN<y>, [7:0] BLUE<y>
0xBF8 BGCLUT.254
  [31:24] ALPHA<y>, [23:16] RED<y>, [15:8] GREEN<y>, [7:0] BLUE<y>
0xBFC BGCLUT.255
  [31:24] ALPHA<y>, [23:16] RED<y>, [15:8] GREEN<y>, [7:0] BLUE<y>
